VERSION 5.7 ;
  NOWIREEXTENSIONATPIN ON ;
  DIVIDERCHAR "/" ;
  BUSBITCHARS "[]" ;
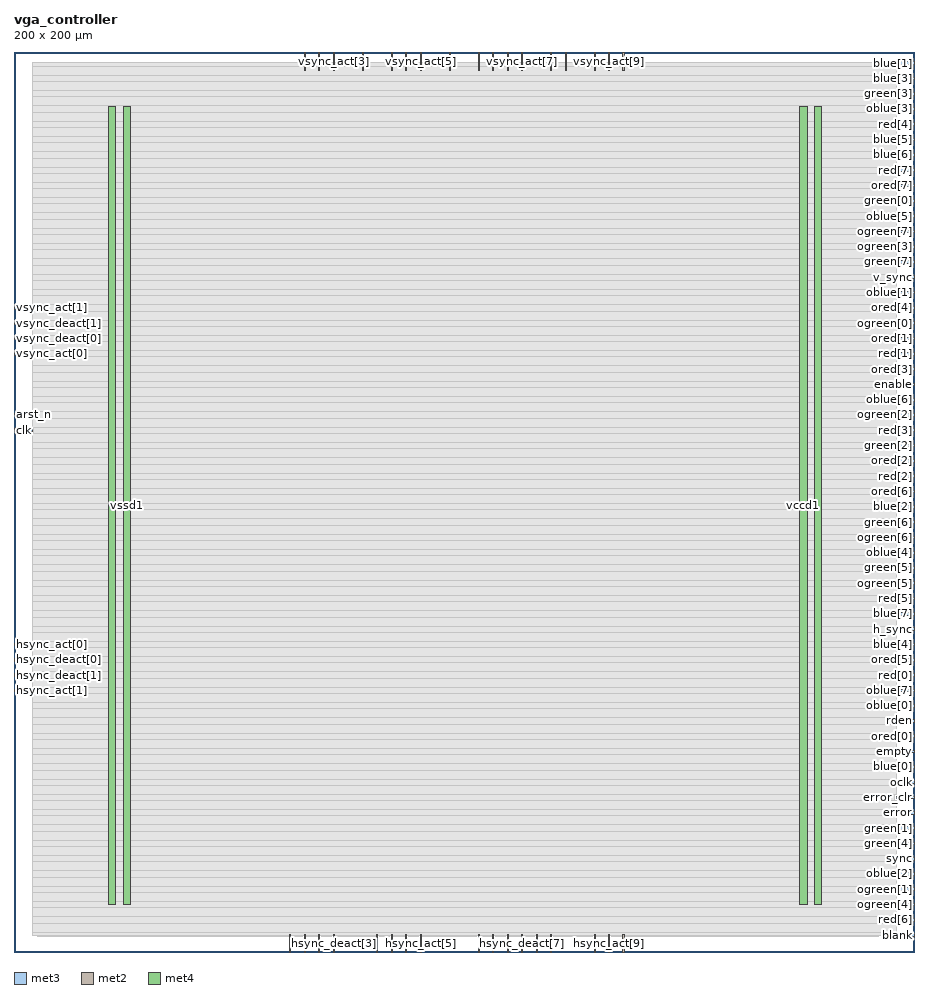
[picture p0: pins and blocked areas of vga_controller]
MACRO vga_controller
  CLASS BLOCK ;
  FOREIGN vga_controller ;
  ORIGIN 0.000 0.000 ;
  SIZE 200.000 BY 200.000 ;
  PIN arst_n
    DIRECTION INPUT ;
    USE SIGNAL ;
    ANTENNAGATEAREA 0.647700 ;
    ANTENNADIFFAREA 0.434700 ;
    PORT
      LAYER met3 ;
        RECT 0.000 119.040 4.000 119.640 ;
    END
  END arst_n
  PIN blank
    DIRECTION OUTPUT ;
    USE SIGNAL ;
    ANTENNADIFFAREA 2.673000 ;
    PORT
      LAYER met3 ;
        RECT 196.000 3.440 200.000 4.040 ;
    END
  END blank
  PIN blue[0]
    DIRECTION INPUT ;
    USE SIGNAL ;
    ANTENNAGATEAREA 0.631200 ;
    ANTENNADIFFAREA 0.434700 ;
    PORT
      LAYER met3 ;
        RECT 196.000 40.840 200.000 41.440 ;
    END
  END blue[0]
  PIN blue[1]
    DIRECTION INPUT ;
    USE SIGNAL ;
    ANTENNAGATEAREA 0.631200 ;
    ANTENNADIFFAREA 0.434700 ;
    PORT
      LAYER met3 ;
        RECT 196.000 197.240 200.000 197.840 ;
    END
  END blue[1]
  PIN blue[2]
    DIRECTION INPUT ;
    USE SIGNAL ;
    ANTENNAGATEAREA 0.631200 ;
    ANTENNADIFFAREA 0.434700 ;
    PORT
      LAYER met3 ;
        RECT 196.000 98.640 200.000 99.240 ;
    END
  END blue[2]
  PIN blue[3]
    DIRECTION INPUT ;
    USE SIGNAL ;
    ANTENNAGATEAREA 0.631200 ;
    ANTENNADIFFAREA 0.434700 ;
    PORT
      LAYER met3 ;
        RECT 196.000 193.840 200.000 194.440 ;
    END
  END blue[3]
  PIN blue[4]
    DIRECTION INPUT ;
    USE SIGNAL ;
    ANTENNAGATEAREA 0.631200 ;
    ANTENNADIFFAREA 0.434700 ;
    PORT
      LAYER met3 ;
        RECT 196.000 68.040 200.000 68.640 ;
    END
  END blue[4]
  PIN blue[5]
    DIRECTION INPUT ;
    USE SIGNAL ;
    ANTENNAGATEAREA 0.631200 ;
    ANTENNADIFFAREA 0.434700 ;
    PORT
      LAYER met3 ;
        RECT 196.000 180.240 200.000 180.840 ;
    END
  END blue[5]
  PIN blue[6]
    DIRECTION INPUT ;
    USE SIGNAL ;
    ANTENNAGATEAREA 0.631200 ;
    ANTENNADIFFAREA 0.434700 ;
    PORT
      LAYER met3 ;
        RECT 196.000 176.840 200.000 177.440 ;
    END
  END blue[6]
  PIN blue[7]
    DIRECTION INPUT ;
    USE SIGNAL ;
    ANTENNAGATEAREA 0.631200 ;
    ANTENNADIFFAREA 0.434700 ;
    PORT
      LAYER met3 ;
        RECT 196.000 74.840 200.000 75.440 ;
    END
  END blue[7]
  PIN clk
    DIRECTION INPUT ;
    USE SIGNAL ;
    ANTENNAGATEAREA 1.286700 ;
    ANTENNADIFFAREA 0.434700 ;
    PORT
      LAYER met3 ;
        RECT 0.000 115.640 4.000 116.240 ;
    END
  END clk
  PIN empty
    DIRECTION INPUT ;
    USE SIGNAL ;
    ANTENNAGATEAREA 0.560700 ;
    ANTENNADIFFAREA 0.434700 ;
    PORT
      LAYER met3 ;
        RECT 196.000 44.240 200.000 44.840 ;
    END
  END empty
  PIN enable
    DIRECTION INPUT ;
    USE SIGNAL ;
    ANTENNAGATEAREA 0.631200 ;
    ANTENNADIFFAREA 0.434700 ;
    PORT
      LAYER met3 ;
        RECT 196.000 125.840 200.000 126.440 ;
    END
  END enable
  PIN error
    DIRECTION OUTPUT ;
    USE SIGNAL ;
    ANTENNADIFFAREA 1.782000 ;
    PORT
      LAYER met3 ;
        RECT 196.000 30.640 200.000 31.240 ;
    END
  END error
  PIN error_clr
    DIRECTION INPUT ;
    USE SIGNAL ;
    ANTENNAGATEAREA 0.560700 ;
    ANTENNADIFFAREA 0.434700 ;
    PORT
      LAYER met3 ;
        RECT 196.000 34.040 200.000 34.640 ;
    END
  END error_clr
  PIN green[0]
    DIRECTION INPUT ;
    USE SIGNAL ;
    ANTENNAGATEAREA 0.631200 ;
    ANTENNADIFFAREA 0.434700 ;
    PORT
      LAYER met3 ;
        RECT 196.000 166.640 200.000 167.240 ;
    END
  END green[0]
  PIN green[1]
    DIRECTION INPUT ;
    USE SIGNAL ;
    ANTENNAGATEAREA 0.631200 ;
    ANTENNADIFFAREA 0.434700 ;
    PORT
      LAYER met3 ;
        RECT 196.000 27.240 200.000 27.840 ;
    END
  END green[1]
  PIN green[2]
    DIRECTION INPUT ;
    USE SIGNAL ;
    ANTENNAGATEAREA 0.631200 ;
    ANTENNADIFFAREA 0.434700 ;
    PORT
      LAYER met3 ;
        RECT 196.000 112.240 200.000 112.840 ;
    END
  END green[2]
  PIN green[3]
    DIRECTION INPUT ;
    USE SIGNAL ;
    ANTENNAGATEAREA 0.631200 ;
    ANTENNADIFFAREA 0.434700 ;
    PORT
      LAYER met3 ;
        RECT 196.000 190.440 200.000 191.040 ;
    END
  END green[3]
  PIN green[4]
    DIRECTION INPUT ;
    USE SIGNAL ;
    ANTENNAGATEAREA 0.631200 ;
    ANTENNADIFFAREA 0.434700 ;
    PORT
      LAYER met3 ;
        RECT 196.000 23.840 200.000 24.440 ;
    END
  END green[4]
  PIN green[5]
    DIRECTION INPUT ;
    USE SIGNAL ;
    ANTENNAGATEAREA 0.631200 ;
    ANTENNADIFFAREA 0.434700 ;
    PORT
      LAYER met3 ;
        RECT 196.000 85.040 200.000 85.640 ;
    END
  END green[5]
  PIN green[6]
    DIRECTION INPUT ;
    USE SIGNAL ;
    ANTENNAGATEAREA 0.631200 ;
    ANTENNADIFFAREA 0.434700 ;
    PORT
      LAYER met3 ;
        RECT 196.000 95.240 200.000 95.840 ;
    END
  END green[6]
  PIN green[7]
    DIRECTION INPUT ;
    USE SIGNAL ;
    ANTENNAGATEAREA 0.631200 ;
    ANTENNADIFFAREA 0.434700 ;
    PORT
      LAYER met3 ;
        RECT 196.000 153.040 200.000 153.640 ;
    END
  END green[7]
  PIN h_sync
    DIRECTION OUTPUT ;
    USE SIGNAL ;
    ANTENNADIFFAREA 2.673000 ;
    PORT
      LAYER met3 ;
        RECT 196.000 71.440 200.000 72.040 ;
    END
  END h_sync
  PIN hsync_act[0]
    DIRECTION INPUT ;
    USE SIGNAL ;
    ANTENNAGATEAREA 0.631200 ;
    ANTENNADIFFAREA 0.434700 ;
    PORT
      LAYER met3 ;
        RECT 0.000 68.040 4.000 68.640 ;
    END
  END hsync_act[0]
  PIN hsync_act[10]
    DIRECTION INPUT ;
    USE SIGNAL ;
    ANTENNAGATEAREA 0.631200 ;
    ANTENNADIFFAREA 0.434700 ;
    PORT
      LAYER met2 ;
        RECT 135.330 0.000 135.610 4.000 ;
    END
  END hsync_act[10]
  PIN hsync_act[1]
    DIRECTION INPUT ;
    USE SIGNAL ;
    ANTENNAGATEAREA 1.177200 ;
    ANTENNADIFFAREA 0.434700 ;
    PORT
      LAYER met3 ;
        RECT 0.000 57.840 4.000 58.440 ;
    END
  END hsync_act[1]
  PIN hsync_act[2]
    DIRECTION INPUT ;
    USE SIGNAL ;
    ANTENNAGATEAREA 0.929700 ;
    ANTENNADIFFAREA 0.434700 ;
    PORT
      LAYER met2 ;
        RECT 61.270 0.000 61.550 4.000 ;
    END
  END hsync_act[2]
  PIN hsync_act[3]
    DIRECTION INPUT ;
    USE SIGNAL ;
    ANTENNAGATEAREA 0.631200 ;
    ANTENNADIFFAREA 0.434700 ;
    PORT
      LAYER met2 ;
        RECT 67.710 0.000 67.990 4.000 ;
    END
  END hsync_act[3]
  PIN hsync_act[4]
    DIRECTION INPUT ;
    USE SIGNAL ;
    ANTENNAGATEAREA 0.631200 ;
    ANTENNADIFFAREA 0.434700 ;
    PORT
      LAYER met2 ;
        RECT 80.590 0.000 80.870 4.000 ;
    END
  END hsync_act[4]
  PIN hsync_act[5]
    DIRECTION INPUT ;
    USE SIGNAL ;
    ANTENNAGATEAREA 0.631200 ;
    ANTENNADIFFAREA 0.434700 ;
    PORT
      LAYER met2 ;
        RECT 90.250 0.000 90.530 4.000 ;
    END
  END hsync_act[5]
  PIN hsync_act[6]
    DIRECTION INPUT ;
    USE SIGNAL ;
    ANTENNAGATEAREA 0.631200 ;
    ANTENNADIFFAREA 0.434700 ;
    PORT
      LAYER met2 ;
        RECT 106.350 0.000 106.630 4.000 ;
    END
  END hsync_act[6]
  PIN hsync_act[7]
    DIRECTION INPUT ;
    USE SIGNAL ;
    ANTENNAGATEAREA 0.631200 ;
    ANTENNADIFFAREA 0.434700 ;
    PORT
      LAYER met2 ;
        RECT 109.570 0.000 109.850 4.000 ;
    END
  END hsync_act[7]
  PIN hsync_act[8]
    DIRECTION INPUT ;
    USE SIGNAL ;
    ANTENNAGATEAREA 0.631200 ;
    ANTENNADIFFAREA 0.434700 ;
    PORT
      LAYER met2 ;
        RECT 119.230 0.000 119.510 4.000 ;
    END
  END hsync_act[8]
  PIN hsync_act[9]
    DIRECTION INPUT ;
    USE SIGNAL ;
    ANTENNAGATEAREA 0.631200 ;
    ANTENNADIFFAREA 0.434700 ;
    PORT
      LAYER met2 ;
        RECT 132.110 0.000 132.390 4.000 ;
    END
  END hsync_act[9]
  PIN hsync_deact[0]
    DIRECTION INPUT ;
    USE SIGNAL ;
    ANTENNAGATEAREA 0.647700 ;
    ANTENNADIFFAREA 0.434700 ;
    PORT
      LAYER met3 ;
        RECT 0.000 64.640 4.000 65.240 ;
    END
  END hsync_deact[0]
  PIN hsync_deact[1]
    DIRECTION INPUT ;
    USE SIGNAL ;
    ANTENNAGATEAREA 1.177200 ;
    ANTENNADIFFAREA 0.434700 ;
    PORT
      LAYER met3 ;
        RECT 0.000 61.240 4.000 61.840 ;
    END
  END hsync_deact[1]
  PIN hsync_deact[2]
    DIRECTION INPUT ;
    USE SIGNAL ;
    ANTENNAGATEAREA 1.177200 ;
    ANTENNADIFFAREA 0.434700 ;
    PORT
      LAYER met2 ;
        RECT 64.490 0.000 64.770 4.000 ;
    END
  END hsync_deact[2]
  PIN hsync_deact[3]
    DIRECTION INPUT ;
    USE SIGNAL ;
    ANTENNAGATEAREA 0.631200 ;
    ANTENNADIFFAREA 0.434700 ;
    PORT
      LAYER met2 ;
        RECT 70.930 0.000 71.210 4.000 ;
    END
  END hsync_deact[3]
  PIN hsync_deact[4]
    DIRECTION INPUT ;
    USE SIGNAL ;
    ANTENNAGATEAREA 0.631200 ;
    ANTENNADIFFAREA 0.434700 ;
    PORT
      LAYER met2 ;
        RECT 83.810 0.000 84.090 4.000 ;
    END
  END hsync_deact[4]
  PIN hsync_deact[5]
    DIRECTION INPUT ;
    USE SIGNAL ;
    ANTENNAGATEAREA 0.631200 ;
    ANTENNADIFFAREA 0.434700 ;
    PORT
      LAYER met2 ;
        RECT 87.030 0.000 87.310 4.000 ;
    END
  END hsync_deact[5]
  PIN hsync_deact[6]
    DIRECTION INPUT ;
    USE SIGNAL ;
    ANTENNAGATEAREA 0.631200 ;
    ANTENNADIFFAREA 0.434700 ;
    PORT
      LAYER met2 ;
        RECT 103.130 0.000 103.410 4.000 ;
    END
  END hsync_deact[6]
  PIN hsync_deact[7]
    DIRECTION INPUT ;
    USE SIGNAL ;
    ANTENNAGATEAREA 0.631200 ;
    ANTENNADIFFAREA 0.434700 ;
    PORT
      LAYER met2 ;
        RECT 112.790 0.000 113.070 4.000 ;
    END
  END hsync_deact[7]
  PIN hsync_deact[8]
    DIRECTION INPUT ;
    USE SIGNAL ;
    ANTENNAGATEAREA 0.631200 ;
    ANTENNADIFFAREA 0.434700 ;
    PORT
      LAYER met2 ;
        RECT 116.010 0.000 116.290 4.000 ;
    END
  END hsync_deact[8]
  PIN hsync_deact[9]
    DIRECTION INPUT ;
    USE SIGNAL ;
    ANTENNAGATEAREA 0.631200 ;
    ANTENNADIFFAREA 0.434700 ;
    PORT
      LAYER met2 ;
        RECT 128.890 0.000 129.170 4.000 ;
    END
  END hsync_deact[9]
  PIN oblue[0]
    DIRECTION OUTPUT ;
    USE SIGNAL ;
    ANTENNADIFFAREA 1.782000 ;
    PORT
      LAYER met3 ;
        RECT 196.000 54.440 200.000 55.040 ;
    END
  END oblue[0]
  PIN oblue[1]
    DIRECTION OUTPUT ;
    USE SIGNAL ;
    ANTENNADIFFAREA 1.782000 ;
    PORT
      LAYER met3 ;
        RECT 196.000 146.240 200.000 146.840 ;
    END
  END oblue[1]
  PIN oblue[2]
    DIRECTION OUTPUT ;
    USE SIGNAL ;
    ANTENNADIFFAREA 1.782000 ;
    PORT
      LAYER met3 ;
        RECT 196.000 17.040 200.000 17.640 ;
    END
  END oblue[2]
  PIN oblue[3]
    DIRECTION OUTPUT ;
    USE SIGNAL ;
    ANTENNADIFFAREA 1.782000 ;
    PORT
      LAYER met3 ;
        RECT 196.000 187.040 200.000 187.640 ;
    END
  END oblue[3]
  PIN oblue[4]
    DIRECTION OUTPUT ;
    USE SIGNAL ;
    ANTENNADIFFAREA 1.782000 ;
    PORT
      LAYER met3 ;
        RECT 196.000 88.440 200.000 89.040 ;
    END
  END oblue[4]
  PIN oblue[5]
    DIRECTION OUTPUT ;
    USE SIGNAL ;
    ANTENNADIFFAREA 1.782000 ;
    PORT
      LAYER met3 ;
        RECT 196.000 163.240 200.000 163.840 ;
    END
  END oblue[5]
  PIN oblue[6]
    DIRECTION OUTPUT ;
    USE SIGNAL ;
    ANTENNADIFFAREA 1.782000 ;
    PORT
      LAYER met3 ;
        RECT 196.000 122.440 200.000 123.040 ;
    END
  END oblue[6]
  PIN oblue[7]
    DIRECTION OUTPUT ;
    USE SIGNAL ;
    ANTENNADIFFAREA 1.782000 ;
    PORT
      LAYER met3 ;
        RECT 196.000 57.840 200.000 58.440 ;
    END
  END oblue[7]
  PIN oclk
    DIRECTION OUTPUT ;
    USE SIGNAL ;
    ANTENNADIFFAREA 1.782000 ;
    PORT
      LAYER met3 ;
        RECT 196.000 37.440 200.000 38.040 ;
    END
  END oclk
  PIN ogreen[0]
    DIRECTION OUTPUT ;
    USE SIGNAL ;
    ANTENNADIFFAREA 1.782000 ;
    PORT
      LAYER met3 ;
        RECT 196.000 139.440 200.000 140.040 ;
    END
  END ogreen[0]
  PIN ogreen[1]
    DIRECTION OUTPUT ;
    USE SIGNAL ;
    ANTENNADIFFAREA 1.782000 ;
    PORT
      LAYER met3 ;
        RECT 196.000 13.640 200.000 14.240 ;
    END
  END ogreen[1]
  PIN ogreen[2]
    DIRECTION OUTPUT ;
    USE SIGNAL ;
    ANTENNADIFFAREA 1.782000 ;
    PORT
      LAYER met3 ;
        RECT 196.000 119.040 200.000 119.640 ;
    END
  END ogreen[2]
  PIN ogreen[3]
    DIRECTION OUTPUT ;
    USE SIGNAL ;
    ANTENNADIFFAREA 1.782000 ;
    PORT
      LAYER met3 ;
        RECT 196.000 156.440 200.000 157.040 ;
    END
  END ogreen[3]
  PIN ogreen[4]
    DIRECTION OUTPUT ;
    USE SIGNAL ;
    ANTENNADIFFAREA 1.782000 ;
    PORT
      LAYER met3 ;
        RECT 196.000 10.240 200.000 10.840 ;
    END
  END ogreen[4]
  PIN ogreen[5]
    DIRECTION OUTPUT ;
    USE SIGNAL ;
    ANTENNADIFFAREA 1.782000 ;
    PORT
      LAYER met3 ;
        RECT 196.000 81.640 200.000 82.240 ;
    END
  END ogreen[5]
  PIN ogreen[6]
    DIRECTION OUTPUT ;
    USE SIGNAL ;
    ANTENNADIFFAREA 1.782000 ;
    PORT
      LAYER met3 ;
        RECT 196.000 91.840 200.000 92.440 ;
    END
  END ogreen[6]
  PIN ogreen[7]
    DIRECTION OUTPUT ;
    USE SIGNAL ;
    ANTENNADIFFAREA 1.782000 ;
    PORT
      LAYER met3 ;
        RECT 196.000 159.840 200.000 160.440 ;
    END
  END ogreen[7]
  PIN ored[0]
    DIRECTION OUTPUT ;
    USE SIGNAL ;
    ANTENNADIFFAREA 1.782000 ;
    PORT
      LAYER met3 ;
        RECT 196.000 47.640 200.000 48.240 ;
    END
  END ored[0]
  PIN ored[1]
    DIRECTION OUTPUT ;
    USE SIGNAL ;
    ANTENNADIFFAREA 1.782000 ;
    PORT
      LAYER met3 ;
        RECT 196.000 136.040 200.000 136.640 ;
    END
  END ored[1]
  PIN ored[2]
    DIRECTION OUTPUT ;
    USE SIGNAL ;
    ANTENNADIFFAREA 1.782000 ;
    PORT
      LAYER met3 ;
        RECT 196.000 108.840 200.000 109.440 ;
    END
  END ored[2]
  PIN ored[3]
    DIRECTION OUTPUT ;
    USE SIGNAL ;
    ANTENNADIFFAREA 1.782000 ;
    PORT
      LAYER met3 ;
        RECT 196.000 129.240 200.000 129.840 ;
    END
  END ored[3]
  PIN ored[4]
    DIRECTION OUTPUT ;
    USE SIGNAL ;
    ANTENNADIFFAREA 1.782000 ;
    PORT
      LAYER met3 ;
        RECT 196.000 142.840 200.000 143.440 ;
    END
  END ored[4]
  PIN ored[5]
    DIRECTION OUTPUT ;
    USE SIGNAL ;
    ANTENNADIFFAREA 1.782000 ;
    PORT
      LAYER met3 ;
        RECT 196.000 64.640 200.000 65.240 ;
    END
  END ored[5]
  PIN ored[6]
    DIRECTION OUTPUT ;
    USE SIGNAL ;
    ANTENNADIFFAREA 1.782000 ;
    PORT
      LAYER met3 ;
        RECT 196.000 102.040 200.000 102.640 ;
    END
  END ored[6]
  PIN ored[7]
    DIRECTION OUTPUT ;
    USE SIGNAL ;
    ANTENNADIFFAREA 1.782000 ;
    PORT
      LAYER met3 ;
        RECT 196.000 170.040 200.000 170.640 ;
    END
  END ored[7]
  PIN rden
    DIRECTION OUTPUT ;
    USE SIGNAL ;
    ANTENNADIFFAREA 2.673000 ;
    PORT
      LAYER met3 ;
        RECT 196.000 51.040 200.000 51.640 ;
    END
  END rden
  PIN red[0]
    DIRECTION INPUT ;
    USE SIGNAL ;
    ANTENNAGATEAREA 0.631200 ;
    ANTENNADIFFAREA 0.434700 ;
    PORT
      LAYER met3 ;
        RECT 196.000 61.240 200.000 61.840 ;
    END
  END red[0]
  PIN red[1]
    DIRECTION INPUT ;
    USE SIGNAL ;
    ANTENNAGATEAREA 0.631200 ;
    ANTENNADIFFAREA 0.434700 ;
    PORT
      LAYER met3 ;
        RECT 196.000 132.640 200.000 133.240 ;
    END
  END red[1]
  PIN red[2]
    DIRECTION INPUT ;
    USE SIGNAL ;
    ANTENNAGATEAREA 0.631200 ;
    ANTENNADIFFAREA 0.434700 ;
    PORT
      LAYER met3 ;
        RECT 196.000 105.440 200.000 106.040 ;
    END
  END red[2]
  PIN red[3]
    DIRECTION INPUT ;
    USE SIGNAL ;
    ANTENNAGATEAREA 0.631200 ;
    ANTENNADIFFAREA 0.434700 ;
    PORT
      LAYER met3 ;
        RECT 196.000 115.640 200.000 116.240 ;
    END
  END red[3]
  PIN red[4]
    DIRECTION INPUT ;
    USE SIGNAL ;
    ANTENNAGATEAREA 0.631200 ;
    ANTENNADIFFAREA 0.434700 ;
    PORT
      LAYER met3 ;
        RECT 196.000 183.640 200.000 184.240 ;
    END
  END red[4]
  PIN red[5]
    DIRECTION INPUT ;
    USE SIGNAL ;
    ANTENNAGATEAREA 0.631200 ;
    ANTENNADIFFAREA 0.434700 ;
    PORT
      LAYER met3 ;
        RECT 196.000 78.240 200.000 78.840 ;
    END
  END red[5]
  PIN red[6]
    DIRECTION INPUT ;
    USE SIGNAL ;
    ANTENNAGATEAREA 0.631200 ;
    ANTENNADIFFAREA 0.434700 ;
    PORT
      LAYER met3 ;
        RECT 196.000 6.840 200.000 7.440 ;
    END
  END red[6]
  PIN red[7]
    DIRECTION INPUT ;
    USE SIGNAL ;
    ANTENNAGATEAREA 0.631200 ;
    ANTENNADIFFAREA 0.434700 ;
    PORT
      LAYER met3 ;
        RECT 196.000 173.440 200.000 174.040 ;
    END
  END red[7]
  PIN sync
    DIRECTION OUTPUT ;
    USE SIGNAL ;
    PORT
      LAYER met3 ;
        RECT 196.000 20.440 200.000 21.040 ;
    END
  END sync
  PIN v_sync
    DIRECTION OUTPUT ;
    USE SIGNAL ;
    ANTENNADIFFAREA 2.673000 ;
    PORT
      LAYER met3 ;
        RECT 196.000 149.640 200.000 150.240 ;
    END
  END v_sync
  PIN vccd1
    DIRECTION INOUT ;
    USE POWER ;
    PORT
      LAYER met4 ;
        RECT 21.040 10.640 22.640 187.920 ;
    END
    PORT
      LAYER met4 ;
        RECT 174.640 10.640 176.240 187.920 ;
    END
  END vccd1
  PIN vssd1
    DIRECTION INOUT ;
    USE GROUND ;
    PORT
      LAYER met4 ;
        RECT 24.340 10.640 25.940 187.920 ;
    END
    PORT
      LAYER met4 ;
        RECT 177.940 10.640 179.540 187.920 ;
    END
  END vssd1
  PIN vsync_act[0]
    DIRECTION INPUT ;
    USE SIGNAL ;
    ANTENNAGATEAREA 0.929700 ;
    ANTENNADIFFAREA 0.434700 ;
    PORT
      LAYER met3 ;
        RECT 0.000 132.640 4.000 133.240 ;
    END
  END vsync_act[0]
  PIN vsync_act[10]
    DIRECTION INPUT ;
    USE SIGNAL ;
    ANTENNAGATEAREA 0.631200 ;
    ANTENNADIFFAREA 0.434700 ;
    PORT
      LAYER met2 ;
        RECT 135.330 196.000 135.610 200.000 ;
    END
  END vsync_act[10]
  PIN vsync_act[1]
    DIRECTION INPUT ;
    USE SIGNAL ;
    ANTENNAGATEAREA 0.682200 ;
    ANTENNADIFFAREA 0.434700 ;
    PORT
      LAYER met3 ;
        RECT 0.000 142.840 4.000 143.440 ;
    END
  END vsync_act[1]
  PIN vsync_act[2]
    DIRECTION INPUT ;
    USE SIGNAL ;
    ANTENNAGATEAREA 0.929700 ;
    ANTENNADIFFAREA 0.434700 ;
    PORT
      LAYER met2 ;
        RECT 64.490 196.000 64.770 200.000 ;
    END
  END vsync_act[2]
  PIN vsync_act[3]
    DIRECTION INPUT ;
    USE SIGNAL ;
    ANTENNAGATEAREA 0.631200 ;
    ANTENNADIFFAREA 0.434700 ;
    PORT
      LAYER met2 ;
        RECT 70.930 196.000 71.210 200.000 ;
    END
  END vsync_act[3]
  PIN vsync_act[4]
    DIRECTION INPUT ;
    USE SIGNAL ;
    ANTENNAGATEAREA 0.631200 ;
    ANTENNADIFFAREA 0.434700 ;
    PORT
      LAYER met2 ;
        RECT 83.810 196.000 84.090 200.000 ;
    END
  END vsync_act[4]
  PIN vsync_act[5]
    DIRECTION INPUT ;
    USE SIGNAL ;
    ANTENNAGATEAREA 0.631200 ;
    ANTENNADIFFAREA 0.434700 ;
    PORT
      LAYER met2 ;
        RECT 90.250 196.000 90.530 200.000 ;
    END
  END vsync_act[5]
  PIN vsync_act[6]
    DIRECTION INPUT ;
    USE SIGNAL ;
    ANTENNAGATEAREA 0.631200 ;
    ANTENNADIFFAREA 0.434700 ;
    PORT
      LAYER met2 ;
        RECT 103.130 196.000 103.410 200.000 ;
    END
  END vsync_act[6]
  PIN vsync_act[7]
    DIRECTION INPUT ;
    USE SIGNAL ;
    ANTENNAGATEAREA 0.631200 ;
    ANTENNADIFFAREA 0.434700 ;
    PORT
      LAYER met2 ;
        RECT 112.790 196.000 113.070 200.000 ;
    END
  END vsync_act[7]
  PIN vsync_act[8]
    DIRECTION INPUT ;
    USE SIGNAL ;
    ANTENNAGATEAREA 0.631200 ;
    ANTENNADIFFAREA 0.434700 ;
    PORT
      LAYER met2 ;
        RECT 122.450 196.000 122.730 200.000 ;
    END
  END vsync_act[8]
  PIN vsync_act[9]
    DIRECTION INPUT ;
    USE SIGNAL ;
    ANTENNAGATEAREA 0.631200 ;
    ANTENNADIFFAREA 0.434700 ;
    PORT
      LAYER met2 ;
        RECT 132.110 196.000 132.390 200.000 ;
    END
  END vsync_act[9]
  PIN vsync_deact[0]
    DIRECTION INPUT ;
    USE SIGNAL ;
    ANTENNAGATEAREA 1.177200 ;
    ANTENNADIFFAREA 0.434700 ;
    PORT
      LAYER met3 ;
        RECT 0.000 136.040 4.000 136.640 ;
    END
  END vsync_deact[0]
  PIN vsync_deact[1]
    DIRECTION INPUT ;
    USE SIGNAL ;
    ANTENNAGATEAREA 1.177200 ;
    ANTENNADIFFAREA 0.434700 ;
    PORT
      LAYER met3 ;
        RECT 0.000 139.440 4.000 140.040 ;
    END
  END vsync_deact[1]
  PIN vsync_deact[2]
    DIRECTION INPUT ;
    USE SIGNAL ;
    ANTENNAGATEAREA 1.177200 ;
    ANTENNADIFFAREA 0.434700 ;
    PORT
      LAYER met2 ;
        RECT 67.710 196.000 67.990 200.000 ;
    END
  END vsync_deact[2]
  PIN vsync_deact[3]
    DIRECTION INPUT ;
    USE SIGNAL ;
    ANTENNAGATEAREA 0.560700 ;
    ANTENNADIFFAREA 0.434700 ;
    PORT
      LAYER met2 ;
        RECT 77.370 196.000 77.650 200.000 ;
    END
  END vsync_deact[3]
  PIN vsync_deact[4]
    DIRECTION INPUT ;
    USE SIGNAL ;
    ANTENNAGATEAREA 0.631200 ;
    ANTENNADIFFAREA 0.434700 ;
    PORT
      LAYER met2 ;
        RECT 87.030 196.000 87.310 200.000 ;
    END
  END vsync_deact[4]
  PIN vsync_deact[5]
    DIRECTION INPUT ;
    USE SIGNAL ;
    ANTENNAGATEAREA 0.631200 ;
    ANTENNADIFFAREA 0.434700 ;
    PORT
      LAYER met2 ;
        RECT 96.690 196.000 96.970 200.000 ;
    END
  END vsync_deact[5]
  PIN vsync_deact[6]
    DIRECTION INPUT ;
    USE SIGNAL ;
    ANTENNAGATEAREA 0.631200 ;
    ANTENNADIFFAREA 0.434700 ;
    PORT
      LAYER met2 ;
        RECT 106.350 196.000 106.630 200.000 ;
    END
  END vsync_deact[6]
  PIN vsync_deact[7]
    DIRECTION INPUT ;
    USE SIGNAL ;
    ANTENNAGATEAREA 0.631200 ;
    ANTENNADIFFAREA 0.434700 ;
    PORT
      LAYER met2 ;
        RECT 109.570 196.000 109.850 200.000 ;
    END
  END vsync_deact[7]
  PIN vsync_deact[8]
    DIRECTION INPUT ;
    USE SIGNAL ;
    ANTENNAGATEAREA 0.631200 ;
    ANTENNADIFFAREA 0.434700 ;
    PORT
      LAYER met2 ;
        RECT 119.230 196.000 119.510 200.000 ;
    END
  END vsync_deact[8]
  PIN vsync_deact[9]
    DIRECTION INPUT ;
    USE SIGNAL ;
    ANTENNAGATEAREA 0.631200 ;
    ANTENNADIFFAREA 0.434700 ;
    PORT
      LAYER met2 ;
        RECT 128.890 196.000 129.170 200.000 ;
    END
  END vsync_deact[9]
  OBS
      LAYER nwell ;
        RECT 5.330 10.760 194.310 187.870 ;
      LAYER li1 ;
        RECT 5.520 10.795 194.120 187.765 ;
      LAYER met1 ;
        RECT 5.130 10.640 194.120 187.920 ;
      LAYER met2 ;
        RECT 5.150 195.720 64.210 197.725 ;
        RECT 65.050 195.720 67.430 197.725 ;
        RECT 68.270 195.720 70.650 197.725 ;
        RECT 71.490 195.720 77.090 197.725 ;
        RECT 77.930 195.720 83.530 197.725 ;
        RECT 84.370 195.720 86.750 197.725 ;
        RECT 87.590 195.720 89.970 197.725 ;
        RECT 90.810 195.720 96.410 197.725 ;
        RECT 97.250 195.720 102.850 197.725 ;
        RECT 103.690 195.720 106.070 197.725 ;
        RECT 106.910 195.720 109.290 197.725 ;
        RECT 110.130 195.720 112.510 197.725 ;
        RECT 113.350 195.720 118.950 197.725 ;
        RECT 119.790 195.720 122.170 197.725 ;
        RECT 123.010 195.720 128.610 197.725 ;
        RECT 129.450 195.720 131.830 197.725 ;
        RECT 132.670 195.720 135.050 197.725 ;
        RECT 135.890 195.720 192.190 197.725 ;
        RECT 5.150 4.280 192.190 195.720 ;
        RECT 5.150 3.555 60.990 4.280 ;
        RECT 61.830 3.555 64.210 4.280 ;
        RECT 65.050 3.555 67.430 4.280 ;
        RECT 68.270 3.555 70.650 4.280 ;
        RECT 71.490 3.555 80.310 4.280 ;
        RECT 81.150 3.555 83.530 4.280 ;
        RECT 84.370 3.555 86.750 4.280 ;
        RECT 87.590 3.555 89.970 4.280 ;
        RECT 90.810 3.555 102.850 4.280 ;
        RECT 103.690 3.555 106.070 4.280 ;
        RECT 106.910 3.555 109.290 4.280 ;
        RECT 110.130 3.555 112.510 4.280 ;
        RECT 113.350 3.555 115.730 4.280 ;
        RECT 116.570 3.555 118.950 4.280 ;
        RECT 119.790 3.555 128.610 4.280 ;
        RECT 129.450 3.555 131.830 4.280 ;
        RECT 132.670 3.555 135.050 4.280 ;
        RECT 135.890 3.555 192.190 4.280 ;
      LAYER met3 ;
        RECT 4.000 196.840 195.600 197.705 ;
        RECT 4.000 194.840 196.000 196.840 ;
        RECT 4.000 193.440 195.600 194.840 ;
        RECT 4.000 191.440 196.000 193.440 ;
        RECT 4.000 190.040 195.600 191.440 ;
        RECT 4.000 188.040 196.000 190.040 ;
        RECT 4.000 186.640 195.600 188.040 ;
        RECT 4.000 184.640 196.000 186.640 ;
        RECT 4.000 183.240 195.600 184.640 ;
        RECT 4.000 181.240 196.000 183.240 ;
        RECT 4.000 179.840 195.600 181.240 ;
        RECT 4.000 177.840 196.000 179.840 ;
        RECT 4.000 176.440 195.600 177.840 ;
        RECT 4.000 174.440 196.000 176.440 ;
        RECT 4.000 173.040 195.600 174.440 ;
        RECT 4.000 171.040 196.000 173.040 ;
        RECT 4.000 169.640 195.600 171.040 ;
        RECT 4.000 167.640 196.000 169.640 ;
        RECT 4.000 166.240 195.600 167.640 ;
        RECT 4.000 164.240 196.000 166.240 ;
        RECT 4.000 162.840 195.600 164.240 ;
        RECT 4.000 160.840 196.000 162.840 ;
        RECT 4.000 159.440 195.600 160.840 ;
        RECT 4.000 157.440 196.000 159.440 ;
        RECT 4.000 156.040 195.600 157.440 ;
        RECT 4.000 154.040 196.000 156.040 ;
        RECT 4.000 152.640 195.600 154.040 ;
        RECT 4.000 150.640 196.000 152.640 ;
        RECT 4.000 149.240 195.600 150.640 ;
        RECT 4.000 147.240 196.000 149.240 ;
        RECT 4.000 145.840 195.600 147.240 ;
        RECT 4.000 143.840 196.000 145.840 ;
        RECT 4.400 142.440 195.600 143.840 ;
        RECT 4.000 140.440 196.000 142.440 ;
        RECT 4.400 139.040 195.600 140.440 ;
        RECT 4.000 137.040 196.000 139.040 ;
        RECT 4.400 135.640 195.600 137.040 ;
        RECT 4.000 133.640 196.000 135.640 ;
        RECT 4.400 132.240 195.600 133.640 ;
        RECT 4.000 130.240 196.000 132.240 ;
        RECT 4.000 128.840 195.600 130.240 ;
        RECT 4.000 126.840 196.000 128.840 ;
        RECT 4.000 125.440 195.600 126.840 ;
        RECT 4.000 123.440 196.000 125.440 ;
        RECT 4.000 122.040 195.600 123.440 ;
        RECT 4.000 120.040 196.000 122.040 ;
        RECT 4.400 118.640 195.600 120.040 ;
        RECT 4.000 116.640 196.000 118.640 ;
        RECT 4.400 115.240 195.600 116.640 ;
        RECT 4.000 113.240 196.000 115.240 ;
        RECT 4.000 111.840 195.600 113.240 ;
        RECT 4.000 109.840 196.000 111.840 ;
        RECT 4.000 108.440 195.600 109.840 ;
        RECT 4.000 106.440 196.000 108.440 ;
        RECT 4.000 105.040 195.600 106.440 ;
        RECT 4.000 103.040 196.000 105.040 ;
        RECT 4.000 101.640 195.600 103.040 ;
        RECT 4.000 99.640 196.000 101.640 ;
        RECT 4.000 98.240 195.600 99.640 ;
        RECT 4.000 96.240 196.000 98.240 ;
        RECT 4.000 94.840 195.600 96.240 ;
        RECT 4.000 92.840 196.000 94.840 ;
        RECT 4.000 91.440 195.600 92.840 ;
        RECT 4.000 89.440 196.000 91.440 ;
        RECT 4.000 88.040 195.600 89.440 ;
        RECT 4.000 86.040 196.000 88.040 ;
        RECT 4.000 84.640 195.600 86.040 ;
        RECT 4.000 82.640 196.000 84.640 ;
        RECT 4.000 81.240 195.600 82.640 ;
        RECT 4.000 79.240 196.000 81.240 ;
        RECT 4.000 77.840 195.600 79.240 ;
        RECT 4.000 75.840 196.000 77.840 ;
        RECT 4.000 74.440 195.600 75.840 ;
        RECT 4.000 72.440 196.000 74.440 ;
        RECT 4.000 71.040 195.600 72.440 ;
        RECT 4.000 69.040 196.000 71.040 ;
        RECT 4.400 67.640 195.600 69.040 ;
        RECT 4.000 65.640 196.000 67.640 ;
        RECT 4.400 64.240 195.600 65.640 ;
        RECT 4.000 62.240 196.000 64.240 ;
        RECT 4.400 60.840 195.600 62.240 ;
        RECT 4.000 58.840 196.000 60.840 ;
        RECT 4.400 57.440 195.600 58.840 ;
        RECT 4.000 55.440 196.000 57.440 ;
        RECT 4.000 54.040 195.600 55.440 ;
        RECT 4.000 52.040 196.000 54.040 ;
        RECT 4.000 50.640 195.600 52.040 ;
        RECT 4.000 48.640 196.000 50.640 ;
        RECT 4.000 47.240 195.600 48.640 ;
        RECT 4.000 45.240 196.000 47.240 ;
        RECT 4.000 43.840 195.600 45.240 ;
        RECT 4.000 41.840 196.000 43.840 ;
        RECT 4.000 40.440 195.600 41.840 ;
        RECT 4.000 38.440 196.000 40.440 ;
        RECT 4.000 37.040 195.600 38.440 ;
        RECT 4.000 35.040 196.000 37.040 ;
        RECT 4.000 33.640 195.600 35.040 ;
        RECT 4.000 31.640 196.000 33.640 ;
        RECT 4.000 30.240 195.600 31.640 ;
        RECT 4.000 28.240 196.000 30.240 ;
        RECT 4.000 26.840 195.600 28.240 ;
        RECT 4.000 24.840 196.000 26.840 ;
        RECT 4.000 23.440 195.600 24.840 ;
        RECT 4.000 21.440 196.000 23.440 ;
        RECT 4.000 20.040 195.600 21.440 ;
        RECT 4.000 18.040 196.000 20.040 ;
        RECT 4.000 16.640 195.600 18.040 ;
        RECT 4.000 14.640 196.000 16.640 ;
        RECT 4.000 13.240 195.600 14.640 ;
        RECT 4.000 11.240 196.000 13.240 ;
        RECT 4.000 9.840 195.600 11.240 ;
        RECT 4.000 7.840 196.000 9.840 ;
        RECT 4.000 6.440 195.600 7.840 ;
        RECT 4.000 4.440 196.000 6.440 ;
        RECT 4.000 3.575 195.600 4.440 ;
  END
END vga_controller
END LIBRARY

